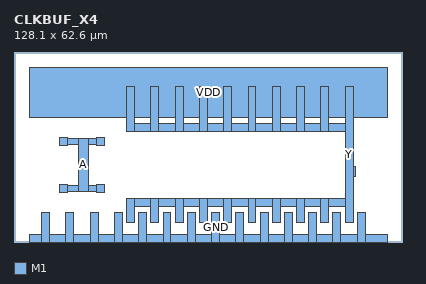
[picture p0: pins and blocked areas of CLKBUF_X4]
MACRO CLKBUF_X4
  CLASS CORE ;
  ORIGIN 0 0 ;
  SIZE 128.100 BY 62.600 ;
  SYMMETRY X Y ;
  SITE TR1um_site ;
  PIN Y
    DIRECTION OUTPUT ;
    USE SIGNAL ;
    PORT
      LAYER M1 ;
        RECT 37.100 6.400 39.700 14.400 ;
      LAYER M1 ;
        RECT 37.100 36.400 39.700 51.200 ;
      LAYER M1 ;
        RECT 39.700 11.800 45.100 14.400 ;
      LAYER M1 ;
        RECT 39.700 36.400 45.100 39.000 ;
      LAYER M1 ;
        RECT 45.100 6.400 47.700 14.400 ;
      LAYER M1 ;
        RECT 45.100 36.400 47.700 51.200 ;
      LAYER M1 ;
        RECT 47.700 11.800 53.100 14.400 ;
      LAYER M1 ;
        RECT 47.700 36.400 53.100 39.000 ;
      LAYER M1 ;
        RECT 53.100 6.400 55.700 14.400 ;
      LAYER M1 ;
        RECT 53.100 36.400 55.700 51.200 ;
      LAYER M1 ;
        RECT 55.700 11.800 61.100 14.400 ;
      LAYER M1 ;
        RECT 55.700 36.400 61.100 39.000 ;
      LAYER M1 ;
        RECT 61.100 6.400 63.700 14.400 ;
      LAYER M1 ;
        RECT 61.100 36.400 63.700 51.200 ;
      LAYER M1 ;
        RECT 63.700 11.800 69.100 14.400 ;
      LAYER M1 ;
        RECT 63.700 36.400 69.100 39.000 ;
      LAYER M1 ;
        RECT 69.100 6.400 71.700 14.400 ;
      LAYER M1 ;
        RECT 69.100 36.400 71.700 51.200 ;
      LAYER M1 ;
        RECT 71.700 11.800 77.100 14.400 ;
      LAYER M1 ;
        RECT 71.700 36.400 77.100 39.000 ;
      LAYER M1 ;
        RECT 77.100 6.400 79.700 14.400 ;
      LAYER M1 ;
        RECT 77.100 36.400 79.700 51.200 ;
      LAYER M1 ;
        RECT 79.700 11.800 85.100 14.400 ;
      LAYER M1 ;
        RECT 79.700 36.400 85.100 39.000 ;
      LAYER M1 ;
        RECT 85.100 6.400 87.700 14.400 ;
      LAYER M1 ;
        RECT 85.100 36.400 87.700 51.200 ;
      LAYER M1 ;
        RECT 87.700 11.800 93.100 14.400 ;
      LAYER M1 ;
        RECT 87.700 36.400 93.100 39.000 ;
      LAYER M1 ;
        RECT 93.100 6.400 95.700 14.400 ;
      LAYER M1 ;
        RECT 93.100 36.400 95.700 51.200 ;
      LAYER M1 ;
        RECT 95.700 11.800 101.100 14.400 ;
      LAYER M1 ;
        RECT 95.700 36.400 101.100 39.000 ;
      LAYER M1 ;
        RECT 101.100 6.400 103.700 14.400 ;
      LAYER M1 ;
        RECT 101.100 36.400 103.700 51.200 ;
      LAYER M1 ;
        RECT 103.700 11.800 109.100 14.400 ;
      LAYER M1 ;
        RECT 103.700 36.400 109.100 39.000 ;
      LAYER M1 ;
        RECT 109.100 6.400 111.700 51.200 ;
      LAYER M1 ;
        RECT 111.700 21.600 112.500 25.000 ;
    END
  END Y
  PIN A
    DIRECTION INPUT ;
    USE SIGNAL ;
    PORT
      LAYER M1 ;
        RECT 15.100 16.400 17.700 19.000 ;
      LAYER M1 ;
        RECT 15.100 31.800 17.700 34.400 ;
      LAYER M1 ;
        RECT 17.700 16.700 21.100 18.700 ;
      LAYER M1 ;
        RECT 17.700 32.100 21.100 34.100 ;
      LAYER M1 ;
        RECT 21.100 16.700 24.500 34.100 ;
      LAYER M1 ;
        RECT 24.500 16.700 27.100 18.700 ;
      LAYER M1 ;
        RECT 24.500 32.100 27.100 34.100 ;
      LAYER M1 ;
        RECT 27.100 16.400 29.700 19.000 ;
      LAYER M1 ;
        RECT 27.100 31.800 29.700 34.400 ;
    END
  END A
  PIN GND
    DIRECTION INOUT ;
    USE GROUND ;
    PORT
      LAYER M1 ;
        RECT 5.000 0.000 9.100 2.600 ;
      LAYER M1 ;
        RECT 9.100 0.000 11.700 9.800 ;
      LAYER M1 ;
        RECT 11.700 0.000 17.100 2.600 ;
      LAYER M1 ;
        RECT 17.100 0.000 19.700 9.800 ;
      LAYER M1 ;
        RECT 19.700 0.000 25.100 2.600 ;
      LAYER M1 ;
        RECT 25.100 0.000 27.700 9.800 ;
      LAYER M1 ;
        RECT 27.700 0.000 33.100 2.600 ;
      LAYER M1 ;
        RECT 33.100 0.000 35.700 9.800 ;
      LAYER M1 ;
        RECT 35.700 0.000 41.100 2.600 ;
      LAYER M1 ;
        RECT 41.100 0.000 43.700 9.800 ;
      LAYER M1 ;
        RECT 43.700 0.000 49.100 2.600 ;
      LAYER M1 ;
        RECT 49.100 0.000 51.700 9.800 ;
      LAYER M1 ;
        RECT 51.700 0.000 57.100 2.600 ;
      LAYER M1 ;
        RECT 57.100 0.000 59.700 9.800 ;
      LAYER M1 ;
        RECT 59.700 0.000 65.100 2.600 ;
      LAYER M1 ;
        RECT 65.100 0.000 67.700 9.800 ;
      LAYER M1 ;
        RECT 67.700 0.000 73.100 2.600 ;
      LAYER M1 ;
        RECT 73.100 0.000 75.700 9.800 ;
      LAYER M1 ;
        RECT 75.700 0.000 81.100 2.600 ;
      LAYER M1 ;
        RECT 81.100 0.000 83.700 9.800 ;
      LAYER M1 ;
        RECT 83.700 0.000 89.100 2.600 ;
      LAYER M1 ;
        RECT 89.100 0.000 91.700 9.800 ;
      LAYER M1 ;
        RECT 91.700 0.000 97.100 2.600 ;
      LAYER M1 ;
        RECT 97.100 0.000 99.700 9.800 ;
      LAYER M1 ;
        RECT 99.700 0.000 105.100 2.600 ;
      LAYER M1 ;
        RECT 105.100 0.000 107.700 9.800 ;
      LAYER M1 ;
        RECT 107.700 0.000 113.100 2.600 ;
      LAYER M1 ;
        RECT 113.100 0.000 115.700 9.800 ;
      LAYER M1 ;
        RECT 115.700 0.000 123.100 2.600 ;
    END
  END GND
  PIN VDD
    DIRECTION INOUT ;
    USE POWER ;
    PORT
      LAYER M1 ;
        RECT 5.000 41.000 123.100 57.600 ;
    END
  END VDD
END CLKBUF_X4
